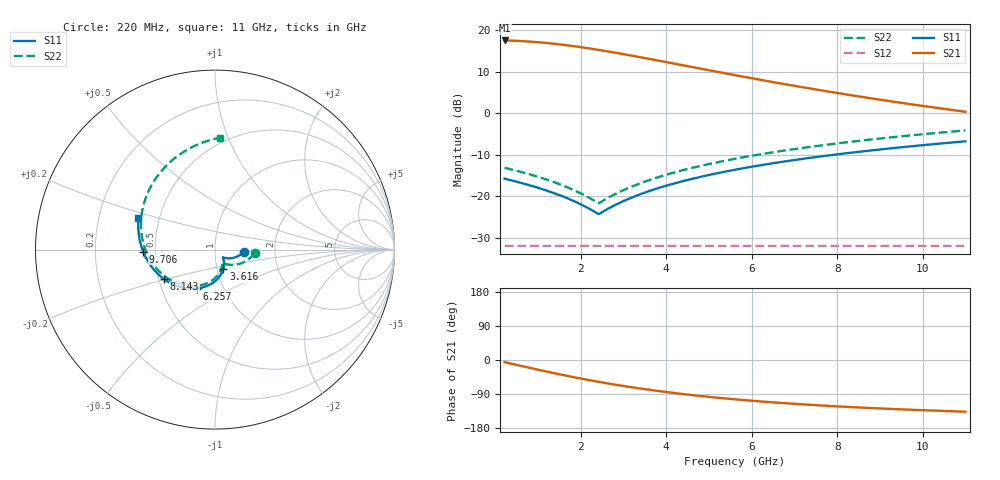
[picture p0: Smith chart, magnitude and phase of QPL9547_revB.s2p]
! written by passband
# GHZ S MA R 50
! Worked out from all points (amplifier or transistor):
!   201 points, 220 MHz to 11 GHz, reference 50 ohm
!   highest |S21| = 17.6 dB at 220 MHz (marker M1)
!   |S21| within 3 dB of that: start of sweep to 2.838 GHz
!   unconditionally stable (mu >= 1): start of sweep to end of sweep
!   at 1.999 GHz: K = 3.18, MAG = 16.1 dB, |S12| = -32.0 dB
!   at 5.61 GHz: K = 6.03, MAG = 9.8 dB, |S12| = -32.0 dB
!   at 11 GHz: K = 9.04, MAG = 3.6 dB, |S12| = -32.0 dB
!   S11 on the Smith chart (normalised r, x): 220 MHz: 1.39, -0.03; 3.616 GHz: 1.07, -0.23; 6.257 GHz: 0.75, -0.34; 8.143 GHz: 0.53, -0.20; 9.706 GHz: 0.43, -0.01; 11 GHz: 0.38, +0.17
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0.22  0.1633 -4.0  7.567 -5.7  0.02512 -5.4  0.2213 -5.5
0.4356  0.1533 -8.0  7.512 -11.3  0.02512 -10.8  0.2077 -10.8
0.6512  0.1432 -12.0  7.423 -16.8  0.02512 -16.1  0.194 -16.1
0.9207  0.1307 -16.9  7.268 -23.6  0.02512 -22.8  0.177 -22.8
1.1902  0.1181 -21.9  7.069 -30.3  0.02512 -29.4  0.16 -29.5
1.6214  0.09799 -29.8  6.679 -40.5  0.02512 -40.1  0.1328 -40.2
2.0526  0.07788 -37.7  6.23 -50.0  0.02512 -50.8  0.1055 -50.9
2.4299  0.06121 -44.7  5.813 -57.8  0.02512 -60.1  0.08293 -60.3
2.7533  0.07629 -50.6  5.451 -64.1  0.02512 -68.1  0.1034 -68.3
3.1845  0.0964 -58.5  4.978 -71.8  0.02512 -78.8  0.1306 -79.0
3.6157  0.1165 -66.5  4.528 -78.8  0.02512 -89.4  0.1578 -89.7
3.8313  0.1266 -70.4  4.314 -82.1  0.02512 -94.8  0.1715 -95.0
4.2086  0.1441 -77.4  3.961 -87.5  0.02512 -104.1  0.1953 -104.4
4.6398  0.1642 -85.3  3.592 -93.0  0.02512 -114.8  0.2225 -115.1
5.1249  0.1869 -94.2  3.219 -98.7  0.02512 -126.8  0.2532 -127.1
5.61  0.2095 -103.1  2.889 -103.8  0.02512 -138.8  0.2838 -139.1
6.2568  0.2396 -115.0  2.51 -109.8  0.02512 -154.7  0.3247 -155.2
7.4426  0.2949 -136.8  1.965 -118.8  0.02512 175.9  0.3996 175.4
8.1433  0.3276 -149.7  1.714 -123.2  0.02512 158.6  0.4438 158.1
9.2213  0.3778 -169.5  1.407 -129.0  0.02512 131.9  0.5119 131.3
9.7064  0.4005 -178.5  1.293 -131.2  0.02512 119.9  0.5426 119.3
11  0.4608 157.8  1.046 -136.4  0.02512 87.9  0.6243 87.2
